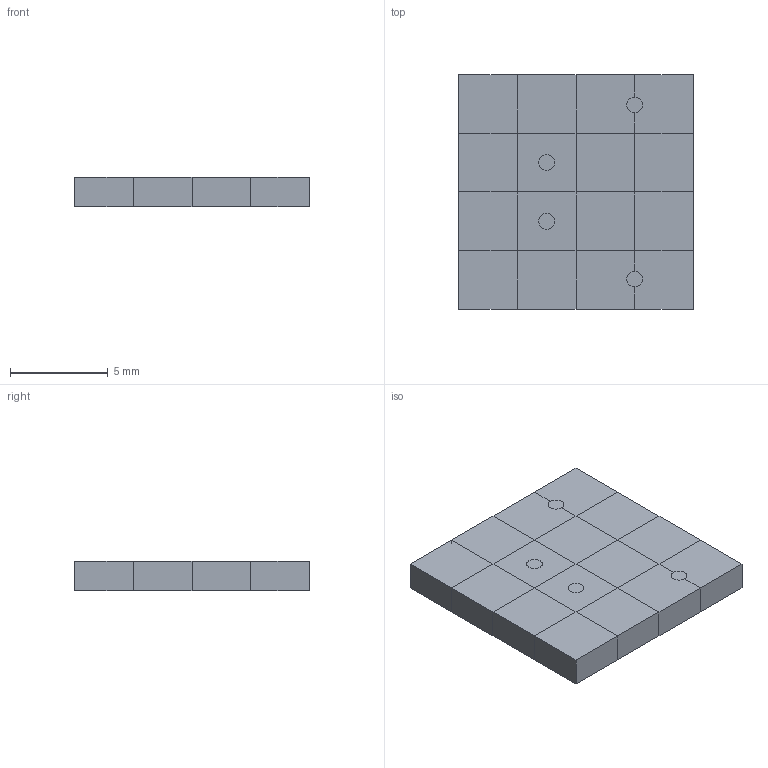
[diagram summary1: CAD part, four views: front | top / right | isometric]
STEP (ISO 10303-21) file: header records copied from the file, then geometry measured from it (millimetres).
FILE_DESCRIPTION(('Open CASCADE Model'),'2;1');
FILE_NAME('Open CASCADE Shape Model','2026-11-27T10:07:43',('Author'),( 'Open CASCADE'),'Open CASCADE STEP processor 7.9','Open CASCADE 7.9' ,'Unknown');
FILE_SCHEMA(('AUTOMOTIVE_DESIGN { 1 0 10303 214 1 1 1 1 }'));
Length unit declared in the file: millimetre
Products named in the file (3): manifold_N11; fluid; solid
Assembly tree (2 placements, depth 2):
  manifold_N11
    fluid
    solid
Bounding box: 12 x 12 x 1.5 mm (x, y, z)
Volume: 216 mm3; surface area: 1165 mm2
Topology: 2 solids, 2 shells, 822 faces, 2544 edges, 1532 vertices
Faces by surface type: plane 814, cylinder 8
Full cylindrical faces by diameter (mm): 0.8 x8
Entity records: 60966 total; most frequent: CARTESIAN_POINT 11135, DIRECTION 9038, LINE 7056, VECTOR 7056, ORIENTED_EDGE 5088, PCURVE 5088, DEFINITIONAL_REPRESENTATION 5088, EDGE_CURVE 2544
One B-rep face of a CAD part: STEP entity #31964.
In plain terms, the planar face has unit normal (0, 0, 1).
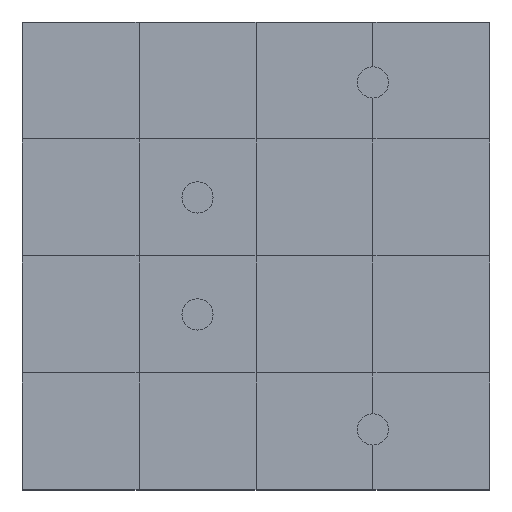
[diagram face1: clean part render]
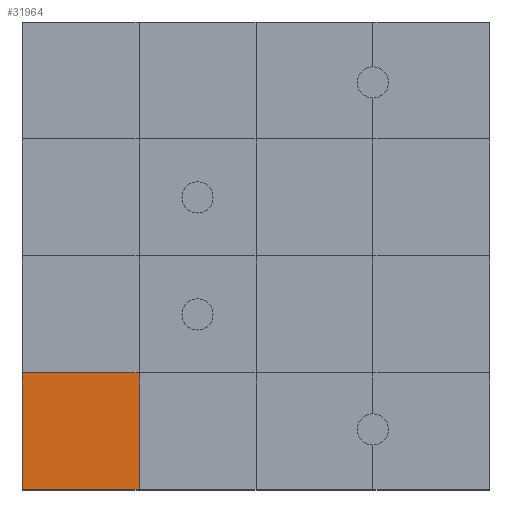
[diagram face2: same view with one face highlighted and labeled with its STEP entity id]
Its self-contained STEP definition (entity closure, numbers rounded to 3 decimals):
#31775 = VERTEX_POINT('',#31776);
#31776 = CARTESIAN_POINT('',(0.,0.,1.5));
#31783 = PLANE('',#31784);
#31784 = AXIS2_PLACEMENT_3D('',#31785,#31786,#31787);
#31785 = CARTESIAN_POINT('',(0.,0.,0.));
#31786 = DIRECTION('',(1.,0.,-0.));
#31787 = DIRECTION('',(0.,0.,1.));
#31795 = PLANE('',#31796);
#31796 = AXIS2_PLACEMENT_3D('',#31797,#31798,#31799);
#31797 = CARTESIAN_POINT('',(0.,0.,0.));
#31798 = DIRECTION('',(-0.,1.,0.));
#31799 = DIRECTION('',(0.,0.,1.));
#31836 = VERTEX_POINT('',#31837);
#31837 = CARTESIAN_POINT('',(0.,3.,1.5));
#31863 = EDGE_CURVE('',#31775,#31836,#31864,.T.);
#31864 = SURFACE_CURVE('',#31865,(#31869,#31876),.PCURVE_S1.);
#31865 = LINE('',#31866,#31867);
#31866 = CARTESIAN_POINT('',(0.,0.,1.5));
#31867 = VECTOR('',#31868,1.);
#31868 = DIRECTION('',(-0.,1.,0.));
#31869 = PCURVE('',#31783,#31870);
#31870 = DEFINITIONAL_REPRESENTATION('',(#31871),#31875);
#31871 = LINE('',#31872,#31873);
#31872 = CARTESIAN_POINT('',(1.5,0.));
#31873 = VECTOR('',#31874,1.);
#31874 = DIRECTION('',(0.,-1.));
#31875 = ( GEOMETRIC_REPRESENTATION_CONTEXT(2) 
PARAMETRIC_REPRESENTATION_CONTEXT() REPRESENTATION_CONTEXT('2D SPACE',''
  ) );
#31876 = PCURVE('',#31877,#31882);
#31877 = PLANE('',#31878);
#31878 = AXIS2_PLACEMENT_3D('',#31879,#31880,#31881);
#31879 = CARTESIAN_POINT('',(0.,0.,1.5));
#31880 = DIRECTION('',(0.,0.,1.));
#31881 = DIRECTION('',(1.,0.,-0.));
#31882 = DEFINITIONAL_REPRESENTATION('',(#31883),#31887);
#31883 = LINE('',#31884,#31885);
#31884 = CARTESIAN_POINT('',(0.,0.));
#31885 = VECTOR('',#31886,1.);
#31886 = DIRECTION('',(0.,1.));
#31887 = ( GEOMETRIC_REPRESENTATION_CONTEXT(2) 
PARAMETRIC_REPRESENTATION_CONTEXT() REPRESENTATION_CONTEXT('2D SPACE',''
  ) );
#31916 = EDGE_CURVE('',#31775,#31917,#31919,.T.);
#31917 = VERTEX_POINT('',#31918);
#31918 = CARTESIAN_POINT('',(3.,0.,1.5));
#31919 = SURFACE_CURVE('',#31920,(#31924,#31931),.PCURVE_S1.);
#31920 = LINE('',#31921,#31922);
#31921 = CARTESIAN_POINT('',(0.,0.,1.5));
#31922 = VECTOR('',#31923,1.);
#31923 = DIRECTION('',(1.,0.,-0.));
#31924 = PCURVE('',#31795,#31925);
#31925 = DEFINITIONAL_REPRESENTATION('',(#31926),#31930);
#31926 = LINE('',#31927,#31928);
#31927 = CARTESIAN_POINT('',(1.5,0.));
#31928 = VECTOR('',#31929,1.);
#31929 = DIRECTION('',(0.,1.));
#31930 = ( GEOMETRIC_REPRESENTATION_CONTEXT(2) 
PARAMETRIC_REPRESENTATION_CONTEXT() REPRESENTATION_CONTEXT('2D SPACE',''
  ) );
#31931 = PCURVE('',#31877,#31932);
#31932 = DEFINITIONAL_REPRESENTATION('',(#31933),#31937);
#31933 = LINE('',#31934,#31935);
#31934 = CARTESIAN_POINT('',(0.,0.));
#31935 = VECTOR('',#31936,1.);
#31936 = DIRECTION('',(1.,0.));
#31937 = ( GEOMETRIC_REPRESENTATION_CONTEXT(2) 
PARAMETRIC_REPRESENTATION_CONTEXT() REPRESENTATION_CONTEXT('2D SPACE',''
  ) );
#31964 = ADVANCED_FACE('',(#31965),#31877,.T.);
#31965 = FACE_BOUND('',#31966,.T.);
#31966 = EDGE_LOOP('',(#31967,#31968,#31969,#31997));
#31967 = ORIENTED_EDGE('',*,*,#31863,.F.);
#31968 = ORIENTED_EDGE('',*,*,#31916,.T.);
#31969 = ORIENTED_EDGE('',*,*,#31970,.T.);
#31970 = EDGE_CURVE('',#31917,#31971,#31973,.T.);
#31971 = VERTEX_POINT('',#31972);
#31972 = CARTESIAN_POINT('',(3.,3.,1.5));
#31973 = SURFACE_CURVE('',#31974,(#31978,#31985),.PCURVE_S1.);
#31974 = LINE('',#31975,#31976);
#31975 = CARTESIAN_POINT('',(3.,0.,1.5));
#31976 = VECTOR('',#31977,1.);
#31977 = DIRECTION('',(-0.,1.,0.));
#31978 = PCURVE('',#31877,#31979);
#31979 = DEFINITIONAL_REPRESENTATION('',(#31980),#31984);
#31980 = LINE('',#31981,#31982);
#31981 = CARTESIAN_POINT('',(3.,0.));
#31982 = VECTOR('',#31983,1.);
#31983 = DIRECTION('',(0.,1.));
#31984 = ( GEOMETRIC_REPRESENTATION_CONTEXT(2) 
PARAMETRIC_REPRESENTATION_CONTEXT() REPRESENTATION_CONTEXT('2D SPACE',''
  ) );
#31985 = PCURVE('',#31986,#31991);
#31986 = PLANE('',#31987);
#31987 = AXIS2_PLACEMENT_3D('',#31988,#31989,#31990);
#31988 = CARTESIAN_POINT('',(3.,0.,1.5));
#31989 = DIRECTION('',(0.,0.,1.));
#31990 = DIRECTION('',(1.,0.,-0.));
#31991 = DEFINITIONAL_REPRESENTATION('',(#31992),#31996);
#31992 = LINE('',#31993,#31994);
#31993 = CARTESIAN_POINT('',(0.,0.));
#31994 = VECTOR('',#31995,1.);
#31995 = DIRECTION('',(0.,1.));
#31996 = ( GEOMETRIC_REPRESENTATION_CONTEXT(2) 
PARAMETRIC_REPRESENTATION_CONTEXT() REPRESENTATION_CONTEXT('2D SPACE',''
  ) );
#31997 = ORIENTED_EDGE('',*,*,#31998,.F.);
#31998 = EDGE_CURVE('',#31836,#31971,#31999,.T.);
#31999 = SURFACE_CURVE('',#32000,(#32004,#32011),.PCURVE_S1.);
#32000 = LINE('',#32001,#32002);
#32001 = CARTESIAN_POINT('',(0.,3.,1.5));
#32002 = VECTOR('',#32003,1.);
#32003 = DIRECTION('',(1.,0.,-0.));
#32004 = PCURVE('',#31877,#32005);
#32005 = DEFINITIONAL_REPRESENTATION('',(#32006),#32010);
#32006 = LINE('',#32007,#32008);
#32007 = CARTESIAN_POINT('',(0.,3.));
#32008 = VECTOR('',#32009,1.);
#32009 = DIRECTION('',(1.,0.));
#32010 = ( GEOMETRIC_REPRESENTATION_CONTEXT(2) 
PARAMETRIC_REPRESENTATION_CONTEXT() REPRESENTATION_CONTEXT('2D SPACE',''
  ) );
#32011 = PCURVE('',#32012,#32017);
#32012 = PLANE('',#32013);
#32013 = AXIS2_PLACEMENT_3D('',#32014,#32015,#32016);
#32014 = CARTESIAN_POINT('',(0.,3.,1.5));
#32015 = DIRECTION('',(0.,0.,1.));
#32016 = DIRECTION('',(1.,0.,-0.));
#32017 = DEFINITIONAL_REPRESENTATION('',(#32018),#32022);
#32018 = LINE('',#32019,#32020);
#32019 = CARTESIAN_POINT('',(0.,0.));
#32020 = VECTOR('',#32021,1.);
#32021 = DIRECTION('',(1.,0.));
#32022 = ( GEOMETRIC_REPRESENTATION_CONTEXT(2) 
PARAMETRIC_REPRESENTATION_CONTEXT() REPRESENTATION_CONTEXT('2D SPACE',''
  ) );
